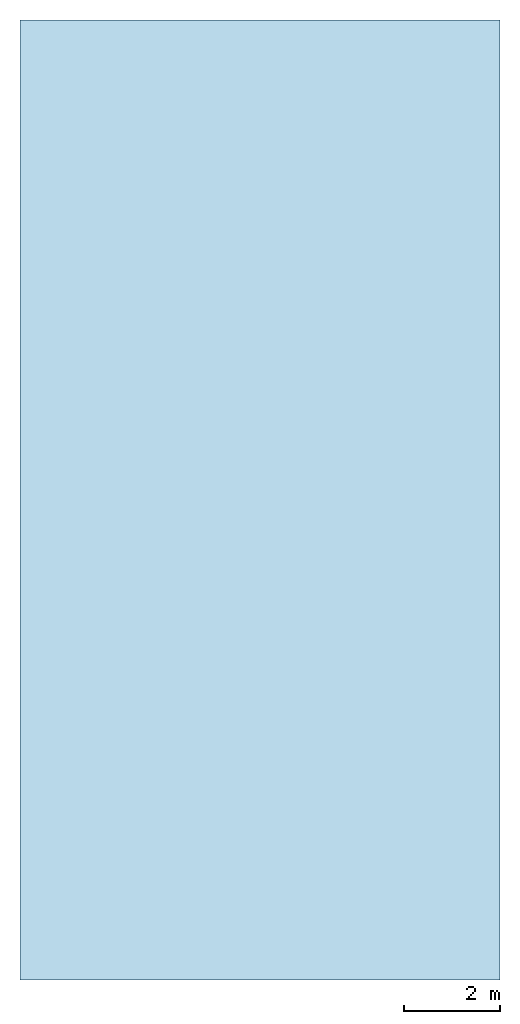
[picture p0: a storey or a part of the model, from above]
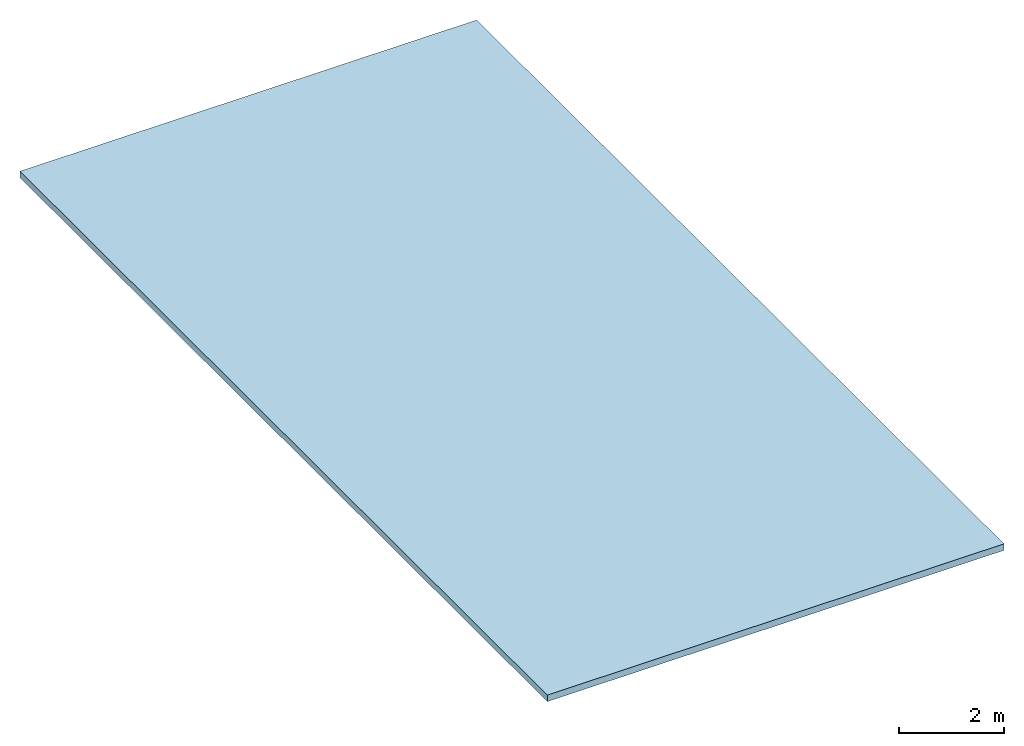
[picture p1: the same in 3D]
Properties of the parts of a building model (IFC2X3)

# File
Description: ViewDefinition [CoordinationView_V2.0], RevitIdentifiers [ContentGUID: fb844429-0b84-487a-bece-f4761d81f242, VersionGUID: 54cb0711-fe8b-47b1-919d-bcc2a3be87fe, NumberOfSaves: 66]
File name: AMANDA-RUN-003-R04-PRESENTATION-20260928.ifc
Time: 2026-09-28T20:57:53-03:00
Written by: ODA SDAI 25.12
Made in: Autodesk - Revit 27.2.0.39 (PTB) - 27.2.0.39

# IfcProject, 0001
LongName: Nome do projeto; Phase: Status do projeto

# IfcSite, Default
RefLatitude: -15, -47, 0, -959472; RefLongitude: -47, -52, -49, -802856; RefElevation: 0 mm

# IfcBuildingStorey (2)
Name | LongName | Elevation (mm)
Nível 1 | Nível 1 | 0
Nível 2 | Nível 2 | 4000

# IfcRoof (4)
In: Nível 1
Material: Telhado padrão 125 mm
Name (Telhado básico:Genérico - 125 mm:...)
330174
330397
330599
330863

# IfcSlab: Piso:Genérico 150 mm (6)
Type - PredefinedType: FLOOR; Material: Material pré-definido de piso 150 mm
Name (Piso:Genérico 150 mm:...) | In
329978 | Nível 1
330024 | Nível 1
330068 | Nível 1
330125 | Nível 1
331163 | Nível 1
331170 | Nível 2

# IfcSlab: Piso:Genérico 150 mm - Preenchido (8)
In: Nível 1
Type - PredefinedType: FLOOR; Material: Material pré-definido de piso 150 mm
Name (Piso:Genérico 150 mm - Preenchido:...)
329943
329950
329957
329964
329971
331095
331108
331177

# IfcSlab: Telhado básico:Genérico - 125 mm (4)
In: Nível 1
Type - PredefinedType: ROOF
Material: Telhado padrão 125 mm
Name (Telhado básico:Genérico - 125 mm:...)
330174
330397
330599
330863
